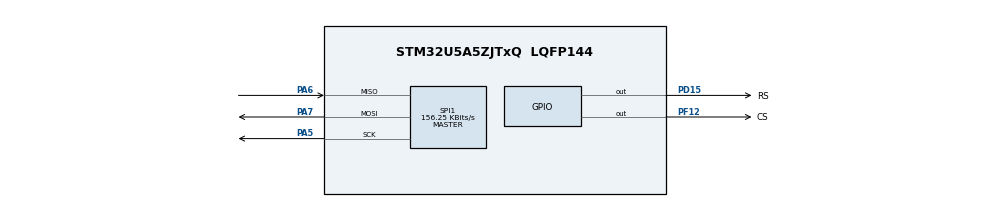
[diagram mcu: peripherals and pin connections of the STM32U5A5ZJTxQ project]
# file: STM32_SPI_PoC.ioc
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CORTEX_M33_NS.userName=CORTEX_M33
Mcu.Family=STM32U5
Mcu.Name=STM32U5A5ZJTxQ
Mcu.Package=LQFP144
NVIC.PriorityGroup=NVIC_PRIORITYGROUP_4
PA5.Mode=Full_Duplex_Master
PA5.Signal=SPI1_SCK
PA6.Mode=Full_Duplex_Master
PA6.Signal=SPI1_MISO
PA7.Mode=Full_Duplex_Master
PA7.Signal=SPI1_MOSI
PD15.GPIO_Label=RS
PD15.Signal=GPIO_Output
PF12.GPIO_Label=CS
PF12.Signal=GPIO_Output
PWR.PowerMode=PWR_SMPS_SUPPLY
ProjectManager.HeapSize=0x200
ProjectManager.StackSize=0x400
ProjectManager.TargetToolchain=STM32CubeIDE
RCC.ADCFreq_Value=16000000
RCC.AHBFreq_Value=160000000
RCC.APB1Freq_Value=160000000
RCC.APB1TimFreq_Value=160000000
RCC.APB2CLKDivider=RCC_HCLK_DIV4
RCC.APB2Freq_Value=40000000
RCC.APB2TimFreq_Value=80000000
RCC.APB3Freq_Value=160000000
RCC.CortexFreq_Value=160000000
RCC.DACCLockSelectionVirtual=RCC_DAC1CLKSOURCE_LSI
RCC.EPOD_VALUE=4000000
RCC.HCLKFreq_Value=160000000
RCC.HSE_VALUE=16000000
RCC.HSI48_VALUE=48000000
RCC.HSI_VALUE=16000000
RCC.LSE_VALUE=32768
RCC.LSIDIV_VALUE=32000
RCC.MSI_VALUE=4000000
RCC.PLLN=80
RCC.SPI1CLockSelection=RCC_SPI1CLKSOURCE_PCLK2
RCC.SYSCLKFreq_VALUE=160000000
RCC.SYSCLKSource=RCC_SYSCLKSOURCE_PLLCLK
RCC.VCOOutputFreq_Value=320000000
SPI1.BaudRatePrescaler=SPI_BAUDRATEPRESCALER_256
SPI1.CalculateBaudRate=156.25 KBits/s
SPI1.DataSize=SPI_DATASIZE_8BIT
SPI1.Direction=SPI_DIRECTION_2LINES
SPI1.Mode=SPI_MODE_MASTER
SPI1.NSSPMode=SPI_NSS_PULSE_DISABLE
SPI1.VirtualType=VM_MASTER
VP_ICACHE_VS_ICACHE.Mode=DirectMappedCache
VP_PWR_VS_DBSignals.Mode=DisableDeadBatterySignals
VP_PWR_VS_LPOM.Mode=PowerOptimisation
VP_PWR_VS_SECSignals.Mode=Security/Privilege
board=NUCLEO-U5A5ZJ-Q

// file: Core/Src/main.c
/* USER CODE BEGIN Header */
/**
  ******************************************************************************
  * @file           : main.c
  * @brief          : Main program body
  ******************************************************************************
  * @attention
  *
  * Copyright (c) 2023 STMicroelectronics.
  * All rights reserved.
  *
  * This software is licensed under terms that can be found in the LICENSE file
  * in the root directory of this software component.
  * If no LICENSE file comes with this software, it is provided AS-IS.
  *
  ******************************************************************************
  */
/* USER CODE END Header */
#include "main.h"

/* USER CODE BEGIN Includes */
#include "lcd.h"
/* USER CODE END Includes */

/* USER CODE BEGIN PD */
#define COUNTOF(__BUFFER__) (sizeof(__BUFFER__) / sizeof(*(__BUFFER__)))
#define BUFFERSIZE (COUNTOF(aTxBuffer) - 1)

/* USER CODE END PD */

SPI_HandleTypeDef hspi1;

void SystemClock_Config(void);
static void SystemPower_Config(void);
static void MX_GPIO_Init(void);
static void MX_ICACHE_Init(void);
static void MX_SPI1_Init(void);

int main(void)
{
  /* USER CODE BEGIN 1 */
  uint8_t aTxBuffer[] = "jan";

  /* USER CODE END 1 */

  /* MCU Configuration--------------------------------------------------------*/

  /* Reset of all peripherals, Initializes the Flash interface and the Systick. */
  HAL_Init();

  /* Configure the system clock */
  SystemClock_Config();

  /* Configure the System Power */
  SystemPower_Config();

  /* Initialize all configured peripherals */
  MX_GPIO_Init();
  MX_ICACHE_Init();
  MX_SPI1_Init();
  /* USER CODE BEGIN 2 */
  LCD_Init(&hspi1);

  /* USER CODE END 2 */

  /* Infinite loop */
  /* USER CODE BEGIN WHILE */
  while (1)
  {
	  HAL_GPIO_WritePin(GPIOD, RS_Pin, GPIO_PIN_SET);
    HAL_GPIO_WritePin(GPIOF, CS_Pin, GPIO_PIN_RESET);
    HAL_SPI_Transmit(&hspi1, (uint8_t *)aTxBuffer, BUFFERSIZE, 200);
    HAL_GPIO_WritePin(GPIOF, CS_Pin, GPIO_PIN_SET);
    HAL_GPIO_WritePin(GPIOD, RS_Pin, GPIO_PIN_RESET);
    HAL_Delay(100);
    /* USER CODE END WHILE */

  }
}

void SystemClock_Config(void)
{
  RCC_OscInitTypeDef RCC_OscInitStruct = {0};
  RCC_ClkInitTypeDef RCC_ClkInitStruct = {0};

  /** Configure the main internal regulator output voltage
  */
  if (HAL_PWREx_ControlVoltageScaling(PWR_REGULATOR_VOLTAGE_SCALE3) != HAL_OK)
  {
    Error_Handler();
  }

  /** Initializes the CPU, AHB and APB buses clocks
  */
  RCC_OscInitStruct.OscillatorType = RCC_OSCILLATORTYPE_MSI;
  RCC_OscInitStruct.MSIState = RCC_MSI_ON;
  RCC_OscInitStruct.MSICalibrationValue = RCC_MSICALIBRATION_DEFAULT;
  RCC_OscInitStruct.MSIClockRange = RCC_MSIRANGE_0;
  RCC_OscInitStruct.PLL.PLLState = RCC_PLL_NONE;
  if (HAL_RCC_OscConfig(&RCC_OscInitStruct) != HAL_OK)
  {
    Error_Handler();
  }

  /** Initializes the CPU, AHB and APB buses clocks
  */
  RCC_ClkInitStruct.ClockType = RCC_CLOCKTYPE_HCLK|RCC_CLOCKTYPE_SYSCLK
                              |RCC_CLOCKTYPE_PCLK1|RCC_CLOCKTYPE_PCLK2
                              |RCC_CLOCKTYPE_PCLK3;
  RCC_ClkInitStruct.SYSCLKSource = RCC_SYSCLKSOURCE_MSI;
  RCC_ClkInitStruct.AHBCLKDivider = RCC_SYSCLK_DIV1;
  RCC_ClkInitStruct.APB1CLKDivider = RCC_HCLK_DIV1;
  RCC_ClkInitStruct.APB2CLKDivider = RCC_HCLK_DIV1;
  RCC_ClkInitStruct.APB3CLKDivider = RCC_HCLK_DIV1;

  if (HAL_RCC_ClockConfig(&RCC_ClkInitStruct, FLASH_LATENCY_1) != HAL_OK)
  {
    Error_Handler();
  }
}

/**
  * @brief Power Configuration
  * @retval None
  */
static void SystemPower_Config(void)
{
  HAL_PWREx_EnableVddIO2();

  /*
   * Disable the internal Pull-Up in Dead Battery pins of UCPD peripheral
   */
  HAL_PWREx_DisableUCPDDeadBattery();

  /*
   * Switch to SMPS regulator instead of LDO
   */
  if (HAL_PWREx_ConfigSupply(PWR_SMPS_SUPPLY) != HAL_OK)
  {
    Error_Handler();
  }
}

static void MX_ICACHE_Init(void)
{

  /** Enable instruction cache in 1-way (direct mapped cache)
  */
  if (HAL_ICACHE_ConfigAssociativityMode(ICACHE_1WAY) != HAL_OK)
  {
    Error_Handler();
  }
  if (HAL_ICACHE_Enable() != HAL_OK)
  {
    Error_Handler();
  }

}

static void MX_SPI1_Init(void)
{

  SPI_AutonomousModeConfTypeDef HAL_SPI_AutonomousMode_Cfg_Struct = {0};

  /* SPI1 parameter configuration*/
  hspi1.Instance = SPI1;
  hspi1.Init.Mode = SPI_MODE_MASTER;
  hspi1.Init.Direction = SPI_DIRECTION_2LINES;
  hspi1.Init.DataSize = SPI_DATASIZE_8BIT;
  hspi1.Init.CLKPolarity = SPI_POLARITY_LOW;
  hspi1.Init.CLKPhase = SPI_PHASE_1EDGE;
  hspi1.Init.NSS = SPI_NSS_SOFT;
  hspi1.Init.BaudRatePrescaler = SPI_BAUDRATEPRESCALER_256;
  hspi1.Init.FirstBit = SPI_FIRSTBIT_MSB;
  hspi1.Init.TIMode = SPI_TIMODE_DISABLE;
  hspi1.Init.CRCCalculation = SPI_CRCCALCULATION_DISABLE;
  hspi1.Init.CRCPolynomial = 0x7;
  hspi1.Init.NSSPMode = SPI_NSS_PULSE_DISABLE;
  hspi1.Init.NSSPolarity = SPI_NSS_POLARITY_LOW;
  hspi1.Init.FifoThreshold = SPI_FIFO_THRESHOLD_01DATA;
  hspi1.Init.MasterSSIdleness = SPI_MASTER_SS_IDLENESS_00CYCLE;
  hspi1.Init.MasterInterDataIdleness = SPI_MASTER_INTERDATA_IDLENESS_00CYCLE;
  hspi1.Init.MasterReceiverAutoSusp = SPI_MASTER_RX_AUTOSUSP_DISABLE;
  hspi1.Init.MasterKeepIOState = SPI_MASTER_KEEP_IO_STATE_DISABLE;
  hspi1.Init.IOSwap = SPI_IO_SWAP_DISABLE;
  hspi1.Init.ReadyMasterManagement = SPI_RDY_MASTER_MANAGEMENT_INTERNALLY;
  hspi1.Init.ReadyPolarity = SPI_RDY_POLARITY_HIGH;
  if (HAL_SPI_Init(&hspi1) != HAL_OK)
  {
    Error_Handler();
  }
  HAL_SPI_AutonomousMode_Cfg_Struct.TriggerState = SPI_AUTO_MODE_DISABLE;
  HAL_SPI_AutonomousMode_Cfg_Struct.TriggerSelection = SPI_GRP1_GPDMA_CH0_TCF_TRG;
  HAL_SPI_AutonomousMode_Cfg_Struct.TriggerPolarity = SPI_TRIG_POLARITY_RISING;
  if (HAL_SPIEx_SetConfigAutonomousMode(&hspi1, &HAL_SPI_AutonomousMode_Cfg_Struct) != HAL_OK)
  {
    Error_Handler();
  }

}

static void MX_GPIO_Init(void)
{
  GPIO_InitTypeDef GPIO_InitStruct = {0};

  /* GPIO Ports Clock Enable */
  __HAL_RCC_GPIOA_CLK_ENABLE();
  __HAL_RCC_GPIOF_CLK_ENABLE();
  __HAL_RCC_GPIOD_CLK_ENABLE();
  __HAL_RCC_GPIOG_CLK_ENABLE();
  __HAL_RCC_GPIOC_CLK_ENABLE();
  __HAL_RCC_GPIOB_CLK_ENABLE();

  /*Configure GPIO pin Output Level */
  HAL_GPIO_WritePin(CS_GPIO_Port, CS_Pin, GPIO_PIN_SET);

  /*Configure GPIO pin Output Level */
  HAL_GPIO_WritePin(RS_GPIO_Port, RS_Pin, GPIO_PIN_RESET);

  /*Configure GPIO pin : CS_Pin */
  GPIO_InitStruct.Pin = CS_Pin;
  GPIO_InitStruct.Mode = GPIO_MODE_OUTPUT_PP;
  GPIO_InitStruct.Pull = GPIO_NOPULL;
  GPIO_InitStruct.Speed = GPIO_SPEED_FREQ_LOW;
  HAL_GPIO_Init(CS_GPIO_Port, &GPIO_InitStruct);

  /*Configure GPIO pin : RS_Pin */
  GPIO_InitStruct.Pin = RS_Pin;
  GPIO_InitStruct.Mode = GPIO_MODE_OUTPUT_PP;
  GPIO_InitStruct.Pull = GPIO_NOPULL;
  GPIO_InitStruct.Speed = GPIO_SPEED_FREQ_LOW;
  HAL_GPIO_Init(RS_GPIO_Port, &GPIO_InitStruct);
}

void Error_Handler(void)
{
  __disable_irq();
  while (1)
  {
  }
}
